VERSION 5.7 ;
  NOWIREEXTENSIONATPIN ON ;
  DIVIDERCHAR "/" ;
  BUSBITCHARS "[]" ;
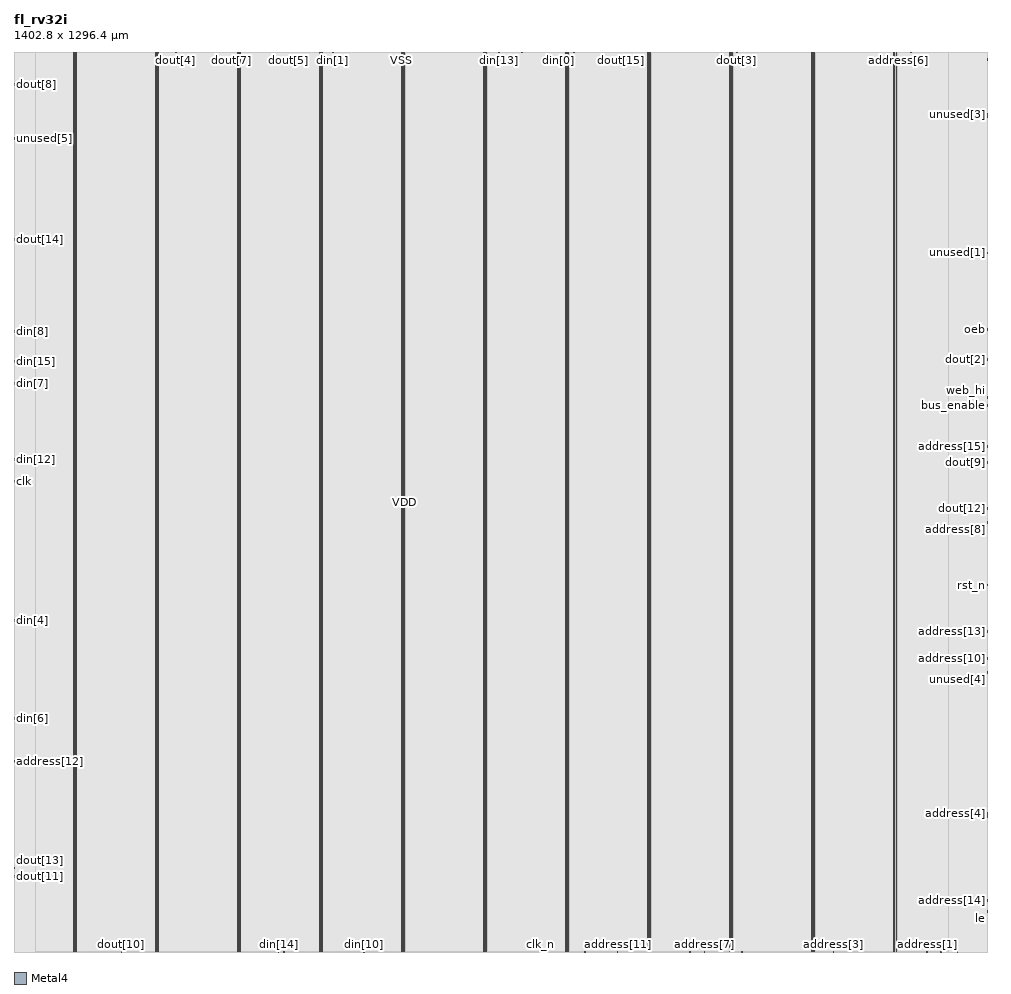
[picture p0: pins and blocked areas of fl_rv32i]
MACRO fl_rv32i
  CLASS BLOCK ;
  FOREIGN fl_rv32i ;
  ORIGIN 0.000 0.000 ;
  SIZE 1402.800 BY 1296.400 ;
  PIN VSS
    DIRECTION INOUT ;
    USE GROUND ;
    PORT
      LAYER Metal4 ;
        RECT 85.540 1.400 86.940 1295.000 ;
    END
    PORT
      LAYER Metal4 ;
        RECT 203.700 1.400 205.100 1295.000 ;
    END
    PORT
      LAYER Metal4 ;
        RECT 321.860 1.400 323.260 1295.000 ;
    END
    PORT
      LAYER Metal4 ;
        RECT 440.020 1.400 441.420 1295.000 ;
    END
    PORT
      LAYER Metal4 ;
        RECT 558.180 1.400 559.580 1295.000 ;
    END
    PORT
      LAYER Metal4 ;
        RECT 676.340 1.400 677.740 1295.000 ;
    END
    PORT
      LAYER Metal4 ;
        RECT 794.500 1.400 795.900 1295.000 ;
    END
    PORT
      LAYER Metal4 ;
        RECT 912.660 1.400 914.060 1295.000 ;
    END
    PORT
      LAYER Metal4 ;
        RECT 1030.820 1.400 1032.220 1295.000 ;
    END
    PORT
      LAYER Metal4 ;
        RECT 1148.980 1.400 1150.380 1295.000 ;
    END
    PORT
      LAYER Metal4 ;
        RECT 1267.140 1.400 1268.540 1295.000 ;
    END
  END VSS
  PIN VDD
    DIRECTION INOUT ;
    USE POWER ;
    PORT
      LAYER Metal4 ;
        RECT 88.900 1.400 90.300 1295.000 ;
    END
    PORT
      LAYER Metal4 ;
        RECT 207.060 1.400 208.460 1295.000 ;
    END
    PORT
      LAYER Metal4 ;
        RECT 325.220 1.400 326.620 1295.000 ;
    END
    PORT
      LAYER Metal4 ;
        RECT 443.380 1.400 444.780 1295.000 ;
    END
    PORT
      LAYER Metal4 ;
        RECT 561.540 1.400 562.940 1295.000 ;
    END
    PORT
      LAYER Metal4 ;
        RECT 679.700 1.400 681.100 1295.000 ;
    END
    PORT
      LAYER Metal4 ;
        RECT 797.860 1.400 799.260 1295.000 ;
    END
    PORT
      LAYER Metal4 ;
        RECT 916.020 1.400 917.420 1295.000 ;
    END
    PORT
      LAYER Metal4 ;
        RECT 1034.180 1.400 1035.580 1295.000 ;
    END
    PORT
      LAYER Metal4 ;
        RECT 1152.340 1.400 1153.740 1295.000 ;
    END
    PORT
      LAYER Metal4 ;
        RECT 1270.500 1.400 1271.900 1295.000 ;
    END
  END VDD
  PIN unused[0]
    DIRECTION OUTPUT ;
    USE SIGNAL ;
    ANTENNADIFFAREA 8.338300 ;
    PORT
      LAYER Metal4 ;
        RECT 1358.560 0.000 1359.120 0.560 ;
    END
  END unused[0]
  PIN unused[1]
    DIRECTION OUTPUT ;
    USE SIGNAL ;
    ANTENNADIFFAREA 8.338300 ;
    PORT
      LAYER Metal4 ;
        RECT 1402.240 1005.480 1402.800 1008.280 ;
    END
  END unused[1]
  PIN unused[2]
    DIRECTION OUTPUT ;
    USE SIGNAL ;
    ANTENNADIFFAREA 8.338300 ;
    PORT
      LAYER Metal4 ;
        RECT 1402.240 1283.800 1402.800 1286.600 ;
    END
  END unused[2]
  PIN unused[3]
    DIRECTION OUTPUT ;
    USE SIGNAL ;
    ANTENNADIFFAREA 8.338300 ;
    PORT
      LAYER Metal4 ;
        RECT 1402.240 1205.400 1402.800 1208.200 ;
    END
  END unused[3]
  PIN unused[4]
    DIRECTION OUTPUT ;
    USE SIGNAL ;
    ANTENNADIFFAREA 8.338300 ;
    PORT
      LAYER Metal4 ;
        RECT 1402.240 401.800 1402.800 404.600 ;
    END
  END unused[4]
  PIN unused[5]
    DIRECTION OUTPUT ;
    USE SIGNAL ;
    ANTENNADIFFAREA 8.338300 ;
    PORT
      LAYER Metal4 ;
        RECT 0.000 1170.120 0.560 1172.920 ;
    END
  END unused[5]
  PIN le
    DIRECTION OUTPUT ;
    USE SIGNAL ;
    ANTENNADIFFAREA 8.338300 ;
    PORT
      LAYER Metal4 ;
        RECT 1402.240 56.840 1402.800 59.640 ;
    END
  END le
  PIN clk
    DIRECTION INPUT ;
    USE SIGNAL ;
    ANTENNAGATEAREA 2.352000 ;
    ANTENNADIFFAREA 0.877000 ;
    PORT
      LAYER Metal4 ;
        RECT 0.000 676.200 0.560 679.000 ;
    END
  END clk
  PIN rst_n
    DIRECTION INPUT ;
    USE SIGNAL ;
    ANTENNAGATEAREA 1.999200 ;
    ANTENNADIFFAREA 0.877000 ;
    PORT
      LAYER Metal4 ;
        RECT 1402.240 527.240 1402.800 530.040 ;
    END
  END rst_n
  PIN clk_n
    DIRECTION INPUT ;
    USE SIGNAL ;
    ANTENNAGATEAREA 2.352000 ;
    ANTENNADIFFAREA 0.877000 ;
    PORT
      LAYER Metal4 ;
        RECT 757.680 0.000 758.240 0.560 ;
    END
  END clk_n
  PIN din[9]
    DIRECTION INPUT ;
    USE SIGNAL ;
    ANTENNAGATEAREA 1.999200 ;
    ANTENNADIFFAREA 0.877000 ;
    PORT
      LAYER Metal4 ;
        RECT 731.360 1295.840 731.920 1296.400 ;
    END
  END din[9]
  PIN din[1]
    DIRECTION INPUT ;
    USE SIGNAL ;
    ANTENNAGATEAREA 1.999200 ;
    ANTENNADIFFAREA 0.877000 ;
    PORT
      LAYER Metal4 ;
        RECT 459.200 1295.840 459.760 1296.400 ;
    END
  END din[1]
  PIN din[4]
    DIRECTION INPUT ;
    USE SIGNAL ;
    ANTENNAGATEAREA 1.999200 ;
    ANTENNADIFFAREA 0.877000 ;
    PORT
      LAYER Metal4 ;
        RECT 0.000 476.280 0.560 479.080 ;
    END
  END din[4]
  PIN din[12]
    DIRECTION INPUT ;
    USE SIGNAL ;
    ANTENNAGATEAREA 1.999200 ;
    ANTENNADIFFAREA 0.877000 ;
    PORT
      LAYER Metal4 ;
        RECT 0.000 707.560 0.560 710.360 ;
    END
  END din[12]
  PIN din[7]
    DIRECTION INPUT ;
    USE SIGNAL ;
    ANTENNAGATEAREA 1.999200 ;
    ANTENNADIFFAREA 0.877000 ;
    PORT
      LAYER Metal4 ;
        RECT 0.000 817.320 0.560 820.120 ;
    END
  END din[7]
  PIN din[10]
    DIRECTION INPUT ;
    USE SIGNAL ;
    ANTENNAGATEAREA 1.999200 ;
    ANTENNADIFFAREA 0.877000 ;
    PORT
      LAYER Metal4 ;
        RECT 504.000 0.000 504.560 0.560 ;
    END
  END din[10]
  PIN din[2]
    DIRECTION INPUT ;
    USE SIGNAL ;
    ANTENNAGATEAREA 1.999200 ;
    ANTENNADIFFAREA 0.877000 ;
    PORT
      LAYER Metal4 ;
        RECT 781.200 1295.840 781.760 1296.400 ;
    END
  END din[2]
  PIN din[11]
    DIRECTION INPUT ;
    USE SIGNAL ;
    ANTENNAGATEAREA 1.999200 ;
    ANTENNADIFFAREA 0.877000 ;
    PORT
      LAYER Metal4 ;
        RECT 752.080 1295.840 752.640 1296.400 ;
    END
  END din[11]
  PIN din[3]
    DIRECTION INPUT ;
    USE SIGNAL ;
    ANTENNAGATEAREA 1.999200 ;
    ANTENNADIFFAREA 0.877000 ;
    PORT
      LAYER Metal4 ;
        RECT 1282.400 1295.840 1282.960 1296.400 ;
    END
  END din[3]
  PIN din[14]
    DIRECTION INPUT ;
    USE SIGNAL ;
    ANTENNAGATEAREA 1.999200 ;
    ANTENNADIFFAREA 0.877000 ;
    PORT
      LAYER Metal4 ;
        RECT 380.800 0.000 381.360 0.560 ;
    END
  END din[14]
  PIN din[6]
    DIRECTION INPUT ;
    USE SIGNAL ;
    ANTENNAGATEAREA 1.999200 ;
    ANTENNADIFFAREA 0.877000 ;
    PORT
      LAYER Metal4 ;
        RECT 0.000 335.160 0.560 337.960 ;
    END
  END din[6]
  PIN din[5]
    DIRECTION INPUT ;
    USE SIGNAL ;
    ANTENNAGATEAREA 1.999200 ;
    ANTENNADIFFAREA 0.877000 ;
    PORT
      LAYER Metal4 ;
        RECT 806.400 1295.840 806.960 1296.400 ;
    END
  END din[5]
  PIN din[0]
    DIRECTION INPUT ;
    USE SIGNAL ;
    ANTENNAGATEAREA 1.999200 ;
    ANTENNADIFFAREA 0.877000 ;
    PORT
      LAYER Metal4 ;
        RECT 784.000 1295.840 784.560 1296.400 ;
    END
  END din[0]
  PIN din[13]
    DIRECTION INPUT ;
    USE SIGNAL ;
    ANTENNAGATEAREA 1.999200 ;
    ANTENNADIFFAREA 0.877000 ;
    PORT
      LAYER Metal4 ;
        RECT 698.320 1295.840 698.880 1296.400 ;
    END
  END din[13]
  PIN web_hi
    DIRECTION OUTPUT ;
    USE SIGNAL ;
    ANTENNADIFFAREA 8.338300 ;
    PORT
      LAYER Metal4 ;
        RECT 1402.240 797.720 1402.800 800.520 ;
    END
  END web_hi
  PIN dout[0]
    DIRECTION OUTPUT ;
    USE SIGNAL ;
    ANTENNADIFFAREA 8.338300 ;
    PORT
      LAYER Metal4 ;
        RECT 822.080 0.000 822.640 0.560 ;
    END
  END dout[0]
  PIN dout[1]
    DIRECTION OUTPUT ;
    USE SIGNAL ;
    ANTENNADIFFAREA 8.338300 ;
    PORT
      LAYER Metal4 ;
        RECT 1291.920 1295.840 1292.480 1296.400 ;
    END
  END dout[1]
  PIN dout[2]
    DIRECTION OUTPUT ;
    USE SIGNAL ;
    ANTENNADIFFAREA 8.338300 ;
    PORT
      LAYER Metal4 ;
        RECT 1402.240 852.600 1402.800 855.400 ;
    END
  END dout[2]
  PIN dout[3]
    DIRECTION OUTPUT ;
    USE SIGNAL ;
    ANTENNADIFFAREA 8.338300 ;
    PORT
      LAYER Metal4 ;
        RECT 1041.040 1295.840 1041.600 1296.400 ;
    END
  END dout[3]
  PIN dout[4]
    DIRECTION OUTPUT ;
    USE SIGNAL ;
    ANTENNADIFFAREA 8.338300 ;
    PORT
      LAYER Metal4 ;
        RECT 232.960 1295.840 233.520 1296.400 ;
    END
  END dout[4]
  PIN dout[5]
    DIRECTION OUTPUT ;
    USE SIGNAL ;
    ANTENNADIFFAREA 8.338300 ;
    PORT
      LAYER Metal4 ;
        RECT 395.360 1295.840 395.920 1296.400 ;
    END
  END dout[5]
  PIN dout[6]
    DIRECTION OUTPUT ;
    USE SIGNAL ;
    ANTENNADIFFAREA 8.338300 ;
    PORT
      LAYER Metal4 ;
        RECT 388.640 0.000 389.200 0.560 ;
    END
  END dout[6]
  PIN dout[7]
    DIRECTION OUTPUT ;
    USE SIGNAL ;
    ANTENNADIFFAREA 8.338300 ;
    PORT
      LAYER Metal4 ;
        RECT 313.040 1295.840 313.600 1296.400 ;
    END
  END dout[7]
  PIN dout[15]
    DIRECTION OUTPUT ;
    USE SIGNAL ;
    ANTENNADIFFAREA 8.338300 ;
    PORT
      LAYER Metal4 ;
        RECT 874.720 1295.840 875.280 1296.400 ;
    END
  END dout[15]
  PIN dout[14]
    DIRECTION OUTPUT ;
    USE SIGNAL ;
    ANTENNADIFFAREA 8.338300 ;
    PORT
      LAYER Metal4 ;
        RECT 0.000 1025.080 0.560 1027.880 ;
    END
  END dout[14]
  PIN dout[13]
    DIRECTION OUTPUT ;
    USE SIGNAL ;
    ANTENNADIFFAREA 8.338300 ;
    PORT
      LAYER Metal4 ;
        RECT 0.000 119.560 0.560 122.360 ;
    END
  END dout[13]
  PIN dout[12]
    DIRECTION OUTPUT ;
    USE SIGNAL ;
    ANTENNADIFFAREA 8.338300 ;
    PORT
      LAYER Metal4 ;
        RECT 1402.240 637.000 1402.800 639.800 ;
    END
  END dout[12]
  PIN dout[11]
    DIRECTION OUTPUT ;
    USE SIGNAL ;
    ANTENNADIFFAREA 8.338300 ;
    PORT
      LAYER Metal4 ;
        RECT 0.000 107.800 0.560 110.600 ;
    END
  END dout[11]
  PIN dout[9]
    DIRECTION OUTPUT ;
    USE SIGNAL ;
    ANTENNADIFFAREA 8.338300 ;
    PORT
      LAYER Metal4 ;
        RECT 1402.240 703.640 1402.800 706.440 ;
    END
  END dout[9]
  PIN dout[8]
    DIRECTION OUTPUT ;
    USE SIGNAL ;
    ANTENNADIFFAREA 8.338300 ;
    PORT
      LAYER Metal4 ;
        RECT 0.000 1248.520 0.560 1251.320 ;
    END
  END dout[8]
  PIN dout[10]
    DIRECTION OUTPUT ;
    USE SIGNAL ;
    ANTENNADIFFAREA 8.338300 ;
    PORT
      LAYER Metal4 ;
        RECT 154.560 0.000 155.120 0.560 ;
    END
  END dout[10]
  PIN address[1]
    DIRECTION OUTPUT ;
    USE SIGNAL ;
    ANTENNADIFFAREA 8.338300 ;
    PORT
      LAYER Metal4 ;
        RECT 1314.880 0.000 1315.440 0.560 ;
    END
  END address[1]
  PIN address[6]
    DIRECTION OUTPUT ;
    USE SIGNAL ;
    ANTENNADIFFAREA 8.338300 ;
    PORT
      LAYER Metal4 ;
        RECT 1274.000 1295.840 1274.560 1296.400 ;
    END
  END address[6]
  PIN address[9]
    DIRECTION OUTPUT ;
    USE SIGNAL ;
    ANTENNADIFFAREA 8.338300 ;
    PORT
      LAYER Metal4 ;
        RECT 1335.040 0.000 1335.600 0.560 ;
    END
  END address[9]
  PIN address[15]
    DIRECTION OUTPUT ;
    USE SIGNAL ;
    ANTENNADIFFAREA 8.338300 ;
    PORT
      LAYER Metal4 ;
        RECT 1402.240 727.160 1402.800 729.960 ;
    END
  END address[15]
  PIN address[14]
    DIRECTION OUTPUT ;
    USE SIGNAL ;
    ANTENNADIFFAREA 8.338300 ;
    PORT
      LAYER Metal4 ;
        RECT 1402.240 72.520 1402.800 75.320 ;
    END
  END address[14]
  PIN address[10]
    DIRECTION OUTPUT ;
    USE SIGNAL ;
    ANTENNADIFFAREA 8.338300 ;
    PORT
      LAYER Metal4 ;
        RECT 1402.240 421.400 1402.800 424.200 ;
    END
  END address[10]
  PIN address[11]
    DIRECTION OUTPUT ;
    USE SIGNAL ;
    ANTENNADIFFAREA 8.338300 ;
    PORT
      LAYER Metal4 ;
        RECT 869.120 0.000 869.680 0.560 ;
    END
  END address[11]
  PIN address[3]
    DIRECTION OUTPUT ;
    USE SIGNAL ;
    ANTENNADIFFAREA 8.338300 ;
    PORT
      LAYER Metal4 ;
        RECT 1180.480 0.000 1181.040 0.560 ;
    END
  END address[3]
  PIN address[4]
    DIRECTION OUTPUT ;
    USE SIGNAL ;
    ANTENNADIFFAREA 8.338300 ;
    PORT
      LAYER Metal4 ;
        RECT 1402.240 197.960 1402.800 200.760 ;
    END
  END address[4]
  PIN address[0]
    DIRECTION OUTPUT ;
    USE SIGNAL ;
    ANTENNADIFFAREA 8.338300 ;
    PORT
      LAYER Metal4 ;
        RECT 1402.240 194.040 1402.800 196.840 ;
    END
  END address[0]
  PIN address[2]
    DIRECTION OUTPUT ;
    USE SIGNAL ;
    ANTENNADIFFAREA 8.338300 ;
    PORT
      LAYER Metal4 ;
        RECT 1048.320 0.000 1048.880 0.560 ;
    END
  END address[2]
  PIN address[5]
    DIRECTION OUTPUT ;
    USE SIGNAL ;
    ANTENNADIFFAREA 8.338300 ;
    PORT
      LAYER Metal4 ;
        RECT 973.280 0.000 973.840 0.560 ;
    END
  END address[5]
  PIN address[13]
    DIRECTION OUTPUT ;
    USE SIGNAL ;
    ANTENNADIFFAREA 8.338300 ;
    PORT
      LAYER Metal4 ;
        RECT 1402.240 460.600 1402.800 463.400 ;
    END
  END address[13]
  PIN address[8]
    DIRECTION OUTPUT ;
    USE SIGNAL ;
    ANTENNADIFFAREA 8.338300 ;
    PORT
      LAYER Metal4 ;
        RECT 1402.240 617.400 1402.800 620.200 ;
    END
  END address[8]
  PIN address[12]
    DIRECTION OUTPUT ;
    USE SIGNAL ;
    ANTENNADIFFAREA 8.338300 ;
    PORT
      LAYER Metal4 ;
        RECT 0.000 272.440 0.560 275.240 ;
    END
  END address[12]
  PIN address[7]
    DIRECTION OUTPUT ;
    USE SIGNAL ;
    ANTENNADIFFAREA 8.338300 ;
    PORT
      LAYER Metal4 ;
        RECT 994.000 0.000 994.560 0.560 ;
    END
  END address[7]
  PIN oeb
    DIRECTION OUTPUT ;
    USE SIGNAL ;
    ANTENNADIFFAREA 8.338300 ;
    PORT
      LAYER Metal4 ;
        RECT 1402.240 895.720 1402.800 898.520 ;
    END
  END oeb
  PIN bus_enable
    DIRECTION OUTPUT ;
    USE SIGNAL ;
    ANTENNADIFFAREA 8.338300 ;
    PORT
      LAYER Metal4 ;
        RECT 1402.240 785.960 1402.800 788.760 ;
    END
  END bus_enable
  PIN din[15]
    DIRECTION INPUT ;
    USE SIGNAL ;
    ANTENNAGATEAREA 1.999200 ;
    ANTENNADIFFAREA 0.877000 ;
    PORT
      LAYER Metal4 ;
        RECT 0.000 848.680 0.560 851.480 ;
    END
  END din[15]
  PIN din[8]
    DIRECTION INPUT ;
    USE SIGNAL ;
    ANTENNAGATEAREA 1.999200 ;
    ANTENNADIFFAREA 0.877000 ;
    PORT
      LAYER Metal4 ;
        RECT 0.000 891.800 0.560 894.600 ;
    END
  END din[8]
  PIN web_lo
    DIRECTION OUTPUT ;
    USE SIGNAL ;
    ANTENNADIFFAREA 8.338300 ;
    PORT
      LAYER Metal4 ;
        RECT 1402.240 1201.480 1402.800 1204.280 ;
    END
  END web_lo
  OBS
      LAYER Nwell ;
        RECT 0.970 0.970 1401.830 1295.430 ;
      LAYER Metal1 ;
        RECT 1.400 1.100 1401.400 1295.300 ;
      LAYER Metal2 ;
        RECT 0.000 0.000 1402.800 1296.400 ;
      LAYER Metal3 ;
        RECT 0.000 0.000 1402.800 1296.400 ;
      LAYER Metal4 ;
        RECT 31.220 1.120 85.240 1295.280 ;
        RECT 87.240 1.120 88.600 1295.280 ;
        RECT 90.600 1.120 203.400 1295.280 ;
        RECT 205.400 1.120 206.760 1295.280 ;
        RECT 208.760 1.120 321.560 1295.280 ;
        RECT 323.560 1.120 324.920 1295.280 ;
        RECT 326.920 1.120 439.720 1295.280 ;
        RECT 441.720 1.120 443.080 1295.280 ;
        RECT 445.080 1.120 557.880 1295.280 ;
        RECT 559.880 1.120 561.240 1295.280 ;
        RECT 563.240 1.120 676.040 1295.280 ;
        RECT 678.040 1.120 679.400 1295.280 ;
        RECT 681.400 1.120 794.200 1295.280 ;
        RECT 796.200 1.120 797.560 1295.280 ;
        RECT 799.560 1.120 912.360 1295.280 ;
        RECT 914.360 1.120 915.720 1295.280 ;
        RECT 917.720 1.120 1030.520 1295.280 ;
        RECT 1032.520 1.120 1033.880 1295.280 ;
        RECT 1035.880 1.120 1148.680 1295.280 ;
        RECT 1150.680 1.120 1152.040 1295.280 ;
        RECT 1154.040 1.120 1266.840 1295.280 ;
        RECT 1268.840 1.120 1270.200 1295.280 ;
        RECT 1272.200 1.120 1346.380 1295.280 ;
  END
END fl_rv32i
END LIBRARY

